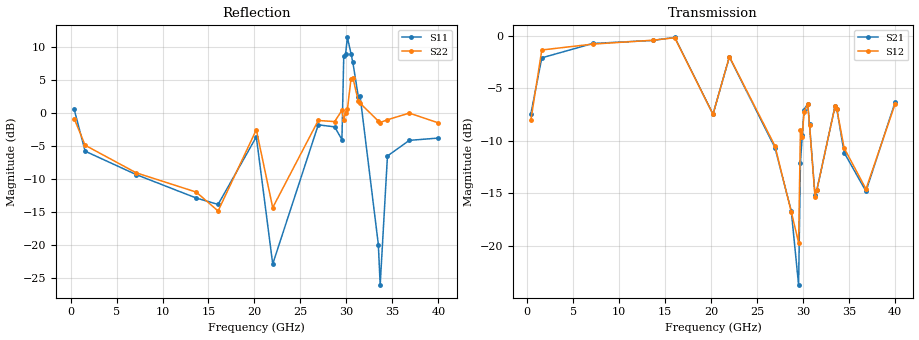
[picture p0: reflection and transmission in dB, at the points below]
! Network Analyzer HP8722ES.07.66: Jul 25, 2000 Serial No. US39175408
! 26 Oct 2004  11:22:33
! Frequency  S11  S21  S12  S22
# HZ  S  DB R  50
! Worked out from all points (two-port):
!   201 points, 400 MHz to 40 GHz, reference 50 ohm
!   highest |S21| = -0.16 dB at 16.04 GHz (marker M1); lowest = -23.8 dB at 29.51 GHz (marker M2)
!   |S21| within 3 dB of the highest: 1.007 GHz to 19.44 GHz (18.44 GHz wide, 180 % of centre); 21.56 GHz to 23.16 GHz (1.604 GHz wide, 7.17 % of centre)
!   lowest |S11| = -26.1 dB at 33.66 GHz (marker M3), VSWR 1.10, Z = 55.2 + j0.613 ohm
!   |S11| at or under -10 dB: 10.65 GHz to 18.19 GHz (7.537 GHz wide, 52.3 % of centre); 21.42 GHz to 23.16 GHz (1.732 GHz wide, 7.77 % of centre); 33.16 GHz to 34.02 GHz (865.7 MHz wide, 2.58 % of centre)
!   |S22| runs from -15.5 to 5.4 dB; largest |S21 - S12| = 0.12
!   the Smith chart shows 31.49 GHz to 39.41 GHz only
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4e8  0.59 -23.9  -7.43 67.1  -8.04 72.3  -0.80 -16.0
1.588e9  -5.74 -71.2  -2.11 24.4  -1.36 24.8  -4.84 -59.5
7.132e9  -9.29 -114.6  -0.74 -15.4  -0.80 -15.9  -9.02 -97.5
1.3666e10  -12.85 -177.7  -0.45 -41.9  -0.43 -42.0  -11.95 -83.3
1.6042e10  -13.83 107.9  -0.16 -56.9  -0.19 -57.2  -14.82 -40.9
2.02e10  -3.57 -56.9  -7.48 -107.4  -7.49 -107.1  -2.49 -19.5
2.1982e10  -22.87 135.0  -2.03 -68.8  -2.00 -68.8  -14.31 -45.3
2.6932e10  -1.74 -55.0  -10.66 -114.8  -10.49 -114.4  -1.08 -1.5
2.8714e10  -2.05 -56.8  -16.71 -73.6  -16.80 -74.3  -1.25 2.6
2.9506e10  -3.98 23.9  -23.76 -143.8  -19.70 -129.3  0.46 25.2
2.9704e10  8.65 -54.9  -12.14 -41.2  -9.02 -33.0  -0.99 -47.7
2.9902e10  9.02 -55.9  -9.50 -11.6  -9.65 -12.9  0.05 19.6
3.01e10  11.53 -70.4  -7.04 -14.1  -7.24 -15.4  0.61 28.3
3.0496e10  9.06 -89.0  -6.47 -55.8  -6.55 -55.1  5.26 -5.6
3.0694e10  7.73 72.9  -8.45 -82.1  -8.52 -78.5  5.42 154.6
3.1288e10  2.55 53.8  -15.17 -63.4  -15.32 -61.7  1.83 141.7
3.1486e10  2.58 -122.0  -14.72 -48.2  -14.72 -47.4  1.53 -35.6
3.3466e10  -19.92 -171.4  -6.71 -38.2  -6.74 -39.0  -1.17 -29.1
3.3664e10  -26.07 6.4  -6.99 -47.7  -7.01 -48.9  -1.39 -27.2
3.4456e10  -6.47 -42.2  -11.13 -59.0  -10.70 -58.3  -0.97 -20.8
3.6832e10  -4.10 -76.6  -14.82 -34.7  -14.61 -34.7  0.04 9.6
4e10  -3.75 -87.1  -6.32 -16.6  -6.50 -16.5  -1.45 -31.2
